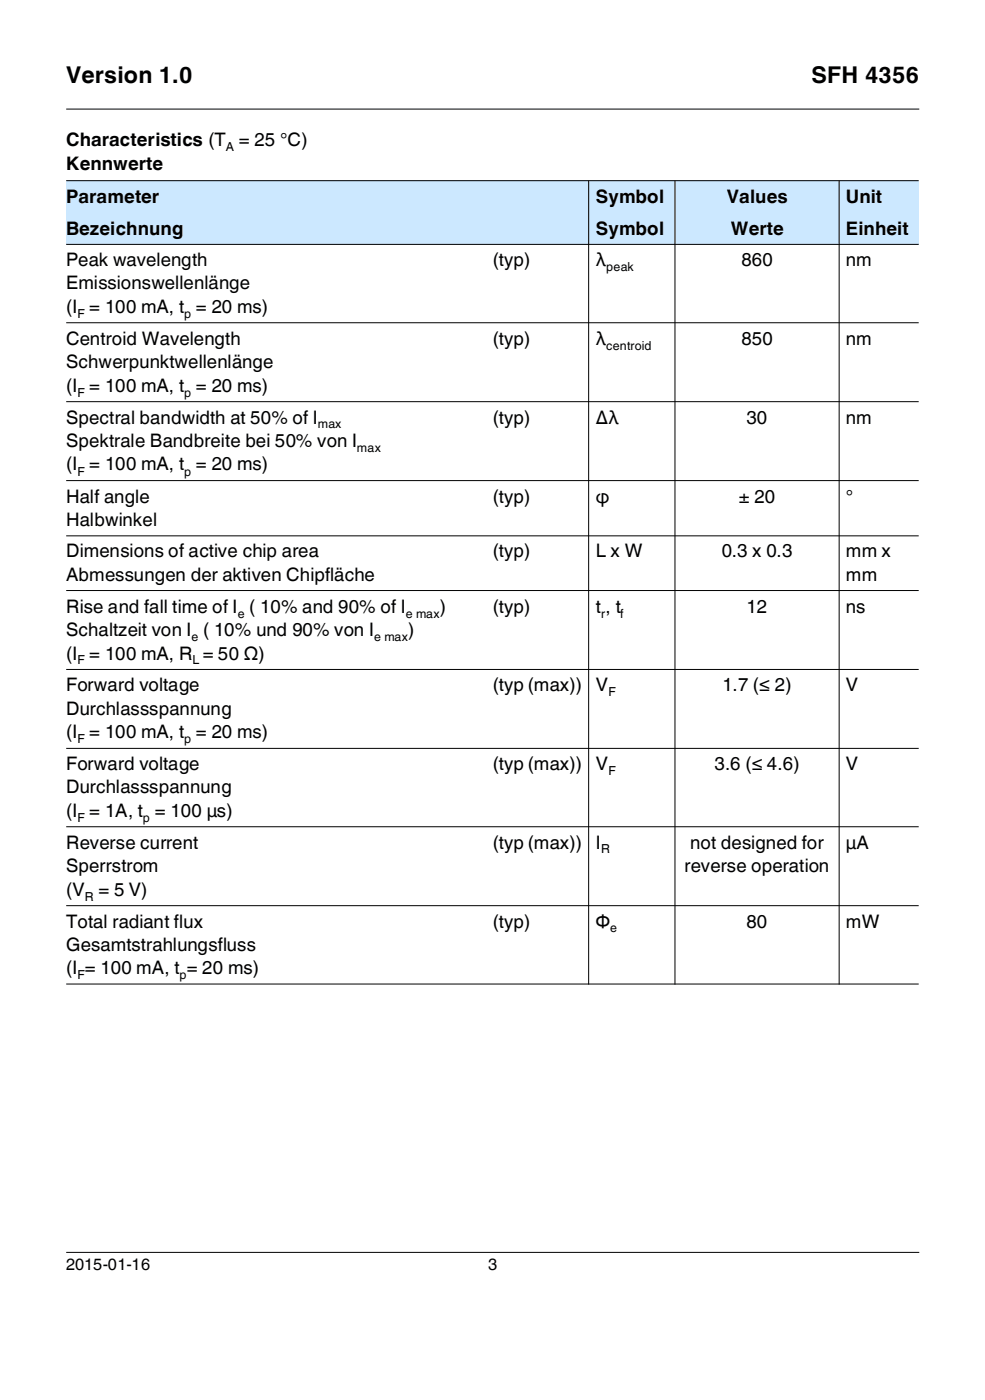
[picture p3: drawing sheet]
<svg xmlns="http://www.w3.org/2000/svg" width="148mm" height="210mm" viewBox="0 0 148 210" stroke-linecap="round" stroke-linejoin="round" font-family="sans-serif">
<defs><g id="words">
<g font-size="3.5">
<text x="9.9" y="12.5">Version 1.0</text>
<text x="121.8" y="12.5">SFH 4356</text>
</g>
<g font-size="2.8">
<text x="9.9" y="22">Characteristics (T = 25 °C)</text>
<text x="9.9" y="25.5">Kennwerte</text>
<text x="9.9" y="30.4">Parameter</text>
<text x="9.9" y="35.3">Bezeichnung</text>
<text x="89.4" y="30.4">Symbol</text>
<text x="89.4" y="35.3">Symbol</text>
<text x="109.1" y="30.4">Values</text>
<text x="109.7" y="35.3">Werte</text>
<text x="126.9" y="30.4">Unit</text>
<text x="126.9" y="35.3">Einheit</text>
<text x="9.9" y="40">Peak wavelength</text>
<text x="73.9" y="40">(typ)</text>
<text x="89.4" y="40">λ</text>
<text x="111.3" y="40">860</text>
<text x="126.9" y="40">nm</text>
<text x="9.9" y="43.5">Emissionswellenlänge</text>
<text x="9.9" y="47">(I = 100 mA, t = 20 ms)</text>
<text x="9.9" y="51.8">Centroid Wavelength</text>
<text x="73.9" y="51.8">(typ)</text>
<text x="89.4" y="51.8">λ</text>
<text x="111.3" y="51.8">850</text>
<text x="126.9" y="51.8">nm</text>
<text x="9.9" y="55.3">Schwerpunktwellenlänge</text>
<text x="9.9" y="58.9">(I = 100 mA, t = 20 ms)</text>
<text x="9.9" y="63.6">Spectral bandwidth at 50% of I</text>
<text x="73.9" y="63.6">(typ)</text>
<text x="89.4" y="63.6">∆λ</text>
<text x="112" y="63.6">30</text>
<text x="126.9" y="63.6">nm</text>
<text x="9.9" y="67.2">Spektrale Bandbreite bei 50% von I</text>
<text x="9.9" y="70.7">(I = 100 mA, t = 20 ms)</text>
<text x="9.9" y="75.5">Half angle</text>
<text x="73.9" y="75.5">(typ)</text>
<text x="89.4" y="75.5">ϕ</text>
<text x="110.9" y="75.5">± 20</text>
<text x="126.9" y="75.5">°</text>
<text x="9.9" y="79">Halbwinkel</text>
<text x="9.9" y="83.7">Dimensions of active chip area</text>
<text x="73.9" y="83.7">(typ)</text>
<text x="89.4" y="83.7">L x W</text>
<text x="108.3" y="83.7">0.3 x 0.3</text>
<text x="126.9" y="83.7">mm x</text>
<text x="9.9" y="87.2">Abmessungen der aktiven Chipfläche</text>
<text x="126.9" y="87.2">mm</text>
<text x="9.9" y="92">Rise and fall time of I ( 10% and 90% of I</text>
<text x="9.9" y="95.5">Schaltzeit von I ( 10% und 90% von I</text>
<text x="61.2" y="95.5">)</text>
<text x="66" y="92">)</text>
<text x="73.9" y="92">(typ)</text>
<text x="89.4" y="92">t , t</text>
<text x="112" y="92">12</text>
<text x="126.9" y="92">ns</text>
<text x="9.9" y="99.1">(I = 100 mA, R = 50 Ω)</text>
<text x="9.9" y="103.8">Forward voltage</text>
<text x="9.9" y="107.4">Durchlassspannung</text>
<text x="73.9" y="103.8">(typ (max))</text>
<text x="89.4" y="103.8">V</text>
<text x="108.4" y="103.8">1.7 (≤ 2)</text>
<text x="126.9" y="103.8">V</text>
<text x="9.9" y="110.9">(I = 100 mA, t = 20 ms)</text>
<text x="9.9" y="115.7">Forward voltage</text>
<text x="9.9" y="119.2">Durchlassspannung</text>
<text x="73.9" y="115.7">(typ (max))</text>
<text x="89.4" y="115.7">V</text>
<text x="107.2" y="115.7">3.6 (≤ 4.6)</text>
<text x="126.9" y="115.7">V</text>
<text x="9.9" y="122.7">(I = 1A, t = 100 µs)</text>
<text x="9.9" y="127.5">Reverse current</text>
<text x="9.9" y="131">Sperrstrom</text>
<text x="73.9" y="127.5">(typ (max))</text>
<text x="89.4" y="127.5">I</text>
<text x="102.7" y="131">reverse operation</text>
<text x="103.6" y="127.5">not designed for</text>
<text x="126.9" y="127.5">µA</text>
<text x="9.9" y="134.5">(V</text>
<text x="14.8" y="134.5">= 5 V)</text>
<text x="9.9" y="139.3">Total radiant flux</text>
<text x="9.9" y="142.8">Gesamtstrahlungsfluss</text>
<text x="73.9" y="139.3">(typ)</text>
<text x="89.4" y="139.3">Φ</text>
<text x="112" y="139.3">80</text>
<text x="126.9" y="139.3">mW</text>
<text x="9.9" y="146.3">(I = 100 mA, t = 20 ms)</text>
</g>
<g font-size="2.5">
<text x="9.9" y="190.8">2015-01-16</text>
<text x="73.3" y="190.8">3</text>
</g>
<g font-size="1.9">
<text x="33.9" y="22.7">A</text>
<text x="91" y="40.7">peak</text>
<text x="11.6" y="47.7">F</text>
<text x="27.6" y="47.7">p</text>
<text x="91" y="52.5">centroid</text>
<text x="11.6" y="59.6">F</text>
<text x="27.6" y="59.6">p</text>
<text x="47.7" y="64.3">max</text>
<text x="11.6" y="71.4">F</text>
<text x="27.6" y="71.4">p</text>
<text x="53.5" y="67.9">max</text>
<text x="35.7" y="92.8">e</text>
<text x="60.9" y="92.8">e max</text>
<text x="90.2" y="92.8">r</text>
<text x="93.1" y="92.8">f</text>
<text x="11.6" y="99.8">F</text>
<text x="28.7" y="96.2">e</text>
<text x="28.9" y="99.8">L</text>
<text x="56.2" y="96.2">e max</text>
<text x="91.3" y="104.5">F</text>
<text x="11.6" y="111.6">F</text>
<text x="27.6" y="111.6">p</text>
<text x="91.3" y="116.4">F</text>
<text x="11.6" y="123.4">F</text>
<text x="21.4" y="123.4">p</text>
<text x="90.2" y="128.1">R</text>
<text x="12.7" y="135.3">R</text>
<text x="91.6" y="140">e</text>
<text x="11.6" y="147">F</text>
<text x="27" y="147">p</text>
</g>
</g></defs>
<path d="M9.9 16.4h128.1M9.9 188.1h128.1" fill="none" stroke="#000" stroke-width=".15"/>
<g fill="#cce8ff">
<path d="M9.9 27.1h62.9v4.9h-62.9z"/>
<path d="M72.8 27.1h15.5v4.9h-15.5z"/>
<path d="M88.3 27.1h13v4.9h-13z"/>
<path d="M101.3 27.1h24.6v4.9h-24.6z"/>
<path d="M125.9 27.1h12v4.9h-12z"/>
<path d="M9.9 32h62.9v4.7h-62.9z"/>
<path d="M72.8 32h15.5v4.7h-15.5z"/>
<path d="M88.3 32h13v4.7h-13z"/>
<path d="M101.3 32h24.6v4.7h-24.6z"/>
<path d="M125.9 32h12v4.7h-12z"/>
</g>
<g fill="none" stroke="#000" stroke-width=".15">
<path d="M9.9 27.1h128M9.9 36.7h128M88.3 27.1v120.8M101.3 27.1v120.8M125.9 27.1v120.8M9.9 48.5h128M9.9 60.3h128M9.9 72.2h128M9.9 80.5h128M9.9 88.7h128M9.9 100.5h128M9.9 112.4h128"/>
<path d="M9.9 124.2h128M9.9 136h128M9.9 147.8h128"/>
</g>
<use href="#words"/>
</svg>
